# OpenTallas memory compiler (tools/mem_compiler), ASAP7 abstract view
VERSION 5.7 ;
BUSBITCHARS "[]" ;
DIVIDERCHAR "/" ;
PROPERTYDEFINITIONS
  MACRO width INTEGER ;
  MACRO depth INTEGER ;
  MACRO banks INTEGER ;
END PROPERTYDEFINITIONS
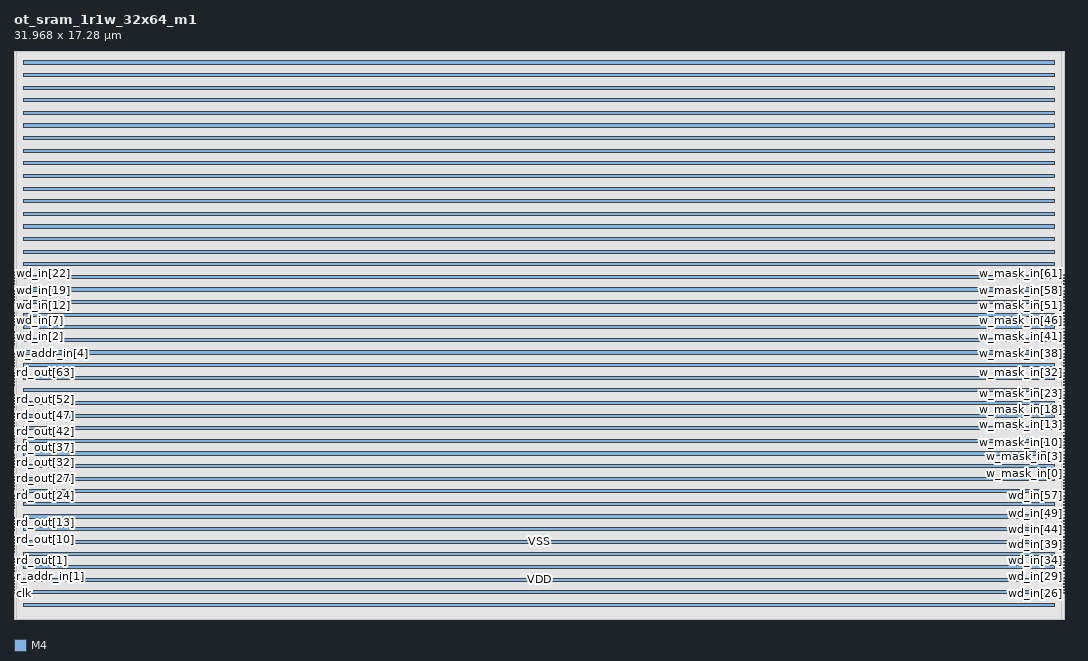
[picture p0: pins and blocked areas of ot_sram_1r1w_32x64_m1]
MACRO ot_sram_1r1w_32x64_m1
  PROPERTY width 64 ;
  PROPERTY depth 32 ;
  PROPERTY banks 1 ;
  FOREIGN ot_sram_1r1w_32x64_m1 0 0 ;
  SYMMETRY X Y R90 ;
  SIZE 31.968 BY 17.280 ;
  CLASS BLOCK ;
  PIN clk
    DIRECTION INPUT ;
    USE CLOCK ;
    SHAPE ABUTMENT ;
    PORT
      LAYER M4 ;
      RECT 0.000 0.768 0.024 0.792 ;
    END
  END clk
  PIN r_ce_in
    DIRECTION INPUT ;
    USE SIGNAL ;
    SHAPE ABUTMENT ;
    PORT
      LAYER M4 ;
      RECT 0.000 0.864 0.024 0.888 ;
    END
  END r_ce_in
  PIN r_addr_in[0]
    DIRECTION INPUT ;
    USE SIGNAL ;
    SHAPE ABUTMENT ;
    PORT
      LAYER M4 ;
      RECT 0.000 0.960 0.024 0.984 ;
    END
  END r_addr_in[0]
  PIN r_addr_in[1]
    DIRECTION INPUT ;
    USE SIGNAL ;
    SHAPE ABUTMENT ;
    PORT
      LAYER M4 ;
      RECT 0.000 1.056 0.024 1.080 ;
    END
  END r_addr_in[1]
  PIN r_addr_in[2]
    DIRECTION INPUT ;
    USE SIGNAL ;
    SHAPE ABUTMENT ;
    PORT
      LAYER M4 ;
      RECT 0.000 1.152 0.024 1.176 ;
    END
  END r_addr_in[2]
  PIN r_addr_in[3]
    DIRECTION INPUT ;
    USE SIGNAL ;
    SHAPE ABUTMENT ;
    PORT
      LAYER M4 ;
      RECT 0.000 1.248 0.024 1.272 ;
    END
  END r_addr_in[3]
  PIN r_addr_in[4]
    DIRECTION INPUT ;
    USE SIGNAL ;
    SHAPE ABUTMENT ;
    PORT
      LAYER M4 ;
      RECT 0.000 1.344 0.024 1.368 ;
    END
  END r_addr_in[4]
  PIN rd_out[0]
    DIRECTION OUTPUT ;
    USE SIGNAL ;
    SHAPE ABUTMENT ;
    PORT
      LAYER M4 ;
      RECT 0.000 1.440 0.024 1.464 ;
    END
  END rd_out[0]
  PIN rd_out[1]
    DIRECTION OUTPUT ;
    USE SIGNAL ;
    SHAPE ABUTMENT ;
    PORT
      LAYER M4 ;
      RECT 0.000 1.536 0.024 1.560 ;
    END
  END rd_out[1]
  PIN rd_out[2]
    DIRECTION OUTPUT ;
    USE SIGNAL ;
    SHAPE ABUTMENT ;
    PORT
      LAYER M4 ;
      RECT 0.000 1.632 0.024 1.656 ;
    END
  END rd_out[2]
  PIN rd_out[3]
    DIRECTION OUTPUT ;
    USE SIGNAL ;
    SHAPE ABUTMENT ;
    PORT
      LAYER M4 ;
      RECT 0.000 1.728 0.024 1.752 ;
    END
  END rd_out[3]
  PIN rd_out[4]
    DIRECTION OUTPUT ;
    USE SIGNAL ;
    SHAPE ABUTMENT ;
    PORT
      LAYER M4 ;
      RECT 0.000 1.824 0.024 1.848 ;
    END
  END rd_out[4]
  PIN rd_out[5]
    DIRECTION OUTPUT ;
    USE SIGNAL ;
    SHAPE ABUTMENT ;
    PORT
      LAYER M4 ;
      RECT 0.000 1.920 0.024 1.944 ;
    END
  END rd_out[5]
  PIN rd_out[6]
    DIRECTION OUTPUT ;
    USE SIGNAL ;
    SHAPE ABUTMENT ;
    PORT
      LAYER M4 ;
      RECT 0.000 2.016 0.024 2.040 ;
    END
  END rd_out[6]
  PIN rd_out[7]
    DIRECTION OUTPUT ;
    USE SIGNAL ;
    SHAPE ABUTMENT ;
    PORT
      LAYER M4 ;
      RECT 0.000 2.112 0.024 2.136 ;
    END
  END rd_out[7]
  PIN rd_out[8]
    DIRECTION OUTPUT ;
    USE SIGNAL ;
    SHAPE ABUTMENT ;
    PORT
      LAYER M4 ;
      RECT 0.000 2.208 0.024 2.232 ;
    END
  END rd_out[8]
  PIN rd_out[9]
    DIRECTION OUTPUT ;
    USE SIGNAL ;
    SHAPE ABUTMENT ;
    PORT
      LAYER M4 ;
      RECT 0.000 2.304 0.024 2.328 ;
    END
  END rd_out[9]
  PIN rd_out[10]
    DIRECTION OUTPUT ;
    USE SIGNAL ;
    SHAPE ABUTMENT ;
    PORT
      LAYER M4 ;
      RECT 0.000 2.400 0.024 2.424 ;
    END
  END rd_out[10]
  PIN rd_out[11]
    DIRECTION OUTPUT ;
    USE SIGNAL ;
    SHAPE ABUTMENT ;
    PORT
      LAYER M4 ;
      RECT 0.000 2.496 0.024 2.520 ;
    END
  END rd_out[11]
  PIN rd_out[12]
    DIRECTION OUTPUT ;
    USE SIGNAL ;
    SHAPE ABUTMENT ;
    PORT
      LAYER M4 ;
      RECT 0.000 2.592 0.024 2.616 ;
    END
  END rd_out[12]
  PIN rd_out[13]
    DIRECTION OUTPUT ;
    USE SIGNAL ;
    SHAPE ABUTMENT ;
    PORT
      LAYER M4 ;
      RECT 0.000 2.688 0.024 2.712 ;
    END
  END rd_out[13]
  PIN rd_out[14]
    DIRECTION OUTPUT ;
    USE SIGNAL ;
    SHAPE ABUTMENT ;
    PORT
      LAYER M4 ;
      RECT 0.000 2.784 0.024 2.808 ;
    END
  END rd_out[14]
  PIN rd_out[15]
    DIRECTION OUTPUT ;
    USE SIGNAL ;
    SHAPE ABUTMENT ;
    PORT
      LAYER M4 ;
      RECT 0.000 2.880 0.024 2.904 ;
    END
  END rd_out[15]
  PIN rd_out[16]
    DIRECTION OUTPUT ;
    USE SIGNAL ;
    SHAPE ABUTMENT ;
    PORT
      LAYER M4 ;
      RECT 0.000 2.976 0.024 3.000 ;
    END
  END rd_out[16]
  PIN rd_out[17]
    DIRECTION OUTPUT ;
    USE SIGNAL ;
    SHAPE ABUTMENT ;
    PORT
      LAYER M4 ;
      RECT 0.000 3.072 0.024 3.096 ;
    END
  END rd_out[17]
  PIN rd_out[18]
    DIRECTION OUTPUT ;
    USE SIGNAL ;
    SHAPE ABUTMENT ;
    PORT
      LAYER M4 ;
      RECT 0.000 3.168 0.024 3.192 ;
    END
  END rd_out[18]
  PIN rd_out[19]
    DIRECTION OUTPUT ;
    USE SIGNAL ;
    SHAPE ABUTMENT ;
    PORT
      LAYER M4 ;
      RECT 0.000 3.264 0.024 3.288 ;
    END
  END rd_out[19]
  PIN rd_out[20]
    DIRECTION OUTPUT ;
    USE SIGNAL ;
    SHAPE ABUTMENT ;
    PORT
      LAYER M4 ;
      RECT 0.000 3.360 0.024 3.384 ;
    END
  END rd_out[20]
  PIN rd_out[21]
    DIRECTION OUTPUT ;
    USE SIGNAL ;
    SHAPE ABUTMENT ;
    PORT
      LAYER M4 ;
      RECT 0.000 3.456 0.024 3.480 ;
    END
  END rd_out[21]
  PIN rd_out[22]
    DIRECTION OUTPUT ;
    USE SIGNAL ;
    SHAPE ABUTMENT ;
    PORT
      LAYER M4 ;
      RECT 0.000 3.552 0.024 3.576 ;
    END
  END rd_out[22]
  PIN rd_out[23]
    DIRECTION OUTPUT ;
    USE SIGNAL ;
    SHAPE ABUTMENT ;
    PORT
      LAYER M4 ;
      RECT 0.000 3.648 0.024 3.672 ;
    END
  END rd_out[23]
  PIN rd_out[24]
    DIRECTION OUTPUT ;
    USE SIGNAL ;
    SHAPE ABUTMENT ;
    PORT
      LAYER M4 ;
      RECT 0.000 3.744 0.024 3.768 ;
    END
  END rd_out[24]
  PIN rd_out[25]
    DIRECTION OUTPUT ;
    USE SIGNAL ;
    SHAPE ABUTMENT ;
    PORT
      LAYER M4 ;
      RECT 0.000 3.840 0.024 3.864 ;
    END
  END rd_out[25]
  PIN rd_out[26]
    DIRECTION OUTPUT ;
    USE SIGNAL ;
    SHAPE ABUTMENT ;
    PORT
      LAYER M4 ;
      RECT 0.000 3.936 0.024 3.960 ;
    END
  END rd_out[26]
  PIN rd_out[27]
    DIRECTION OUTPUT ;
    USE SIGNAL ;
    SHAPE ABUTMENT ;
    PORT
      LAYER M4 ;
      RECT 0.000 4.032 0.024 4.056 ;
    END
  END rd_out[27]
  PIN rd_out[28]
    DIRECTION OUTPUT ;
    USE SIGNAL ;
    SHAPE ABUTMENT ;
    PORT
      LAYER M4 ;
      RECT 0.000 4.128 0.024 4.152 ;
    END
  END rd_out[28]
  PIN rd_out[29]
    DIRECTION OUTPUT ;
    USE SIGNAL ;
    SHAPE ABUTMENT ;
    PORT
      LAYER M4 ;
      RECT 0.000 4.224 0.024 4.248 ;
    END
  END rd_out[29]
  PIN rd_out[30]
    DIRECTION OUTPUT ;
    USE SIGNAL ;
    SHAPE ABUTMENT ;
    PORT
      LAYER M4 ;
      RECT 0.000 4.320 0.024 4.344 ;
    END
  END rd_out[30]
  PIN rd_out[31]
    DIRECTION OUTPUT ;
    USE SIGNAL ;
    SHAPE ABUTMENT ;
    PORT
      LAYER M4 ;
      RECT 0.000 4.416 0.024 4.440 ;
    END
  END rd_out[31]
  PIN rd_out[32]
    DIRECTION OUTPUT ;
    USE SIGNAL ;
    SHAPE ABUTMENT ;
    PORT
      LAYER M4 ;
      RECT 0.000 4.512 0.024 4.536 ;
    END
  END rd_out[32]
  PIN rd_out[33]
    DIRECTION OUTPUT ;
    USE SIGNAL ;
    SHAPE ABUTMENT ;
    PORT
      LAYER M4 ;
      RECT 0.000 4.608 0.024 4.632 ;
    END
  END rd_out[33]
  PIN rd_out[34]
    DIRECTION OUTPUT ;
    USE SIGNAL ;
    SHAPE ABUTMENT ;
    PORT
      LAYER M4 ;
      RECT 0.000 4.704 0.024 4.728 ;
    END
  END rd_out[34]
  PIN rd_out[35]
    DIRECTION OUTPUT ;
    USE SIGNAL ;
    SHAPE ABUTMENT ;
    PORT
      LAYER M4 ;
      RECT 0.000 4.800 0.024 4.824 ;
    END
  END rd_out[35]
  PIN rd_out[36]
    DIRECTION OUTPUT ;
    USE SIGNAL ;
    SHAPE ABUTMENT ;
    PORT
      LAYER M4 ;
      RECT 0.000 4.896 0.024 4.920 ;
    END
  END rd_out[36]
  PIN rd_out[37]
    DIRECTION OUTPUT ;
    USE SIGNAL ;
    SHAPE ABUTMENT ;
    PORT
      LAYER M4 ;
      RECT 0.000 4.992 0.024 5.016 ;
    END
  END rd_out[37]
  PIN rd_out[38]
    DIRECTION OUTPUT ;
    USE SIGNAL ;
    SHAPE ABUTMENT ;
    PORT
      LAYER M4 ;
      RECT 0.000 5.088 0.024 5.112 ;
    END
  END rd_out[38]
  PIN rd_out[39]
    DIRECTION OUTPUT ;
    USE SIGNAL ;
    SHAPE ABUTMENT ;
    PORT
      LAYER M4 ;
      RECT 0.000 5.184 0.024 5.208 ;
    END
  END rd_out[39]
  PIN rd_out[40]
    DIRECTION OUTPUT ;
    USE SIGNAL ;
    SHAPE ABUTMENT ;
    PORT
      LAYER M4 ;
      RECT 0.000 5.280 0.024 5.304 ;
    END
  END rd_out[40]
  PIN rd_out[41]
    DIRECTION OUTPUT ;
    USE SIGNAL ;
    SHAPE ABUTMENT ;
    PORT
      LAYER M4 ;
      RECT 0.000 5.376 0.024 5.400 ;
    END
  END rd_out[41]
  PIN rd_out[42]
    DIRECTION OUTPUT ;
    USE SIGNAL ;
    SHAPE ABUTMENT ;
    PORT
      LAYER M4 ;
      RECT 0.000 5.472 0.024 5.496 ;
    END
  END rd_out[42]
  PIN rd_out[43]
    DIRECTION OUTPUT ;
    USE SIGNAL ;
    SHAPE ABUTMENT ;
    PORT
      LAYER M4 ;
      RECT 0.000 5.568 0.024 5.592 ;
    END
  END rd_out[43]
  PIN rd_out[44]
    DIRECTION OUTPUT ;
    USE SIGNAL ;
    SHAPE ABUTMENT ;
    PORT
      LAYER M4 ;
      RECT 0.000 5.664 0.024 5.688 ;
    END
  END rd_out[44]
  PIN rd_out[45]
    DIRECTION OUTPUT ;
    USE SIGNAL ;
    SHAPE ABUTMENT ;
    PORT
      LAYER M4 ;
      RECT 0.000 5.760 0.024 5.784 ;
    END
  END rd_out[45]
  PIN rd_out[46]
    DIRECTION OUTPUT ;
    USE SIGNAL ;
    SHAPE ABUTMENT ;
    PORT
      LAYER M4 ;
      RECT 0.000 5.856 0.024 5.880 ;
    END
  END rd_out[46]
  PIN rd_out[47]
    DIRECTION OUTPUT ;
    USE SIGNAL ;
    SHAPE ABUTMENT ;
    PORT
      LAYER M4 ;
      RECT 0.000 5.952 0.024 5.976 ;
    END
  END rd_out[47]
  PIN rd_out[48]
    DIRECTION OUTPUT ;
    USE SIGNAL ;
    SHAPE ABUTMENT ;
    PORT
      LAYER M4 ;
      RECT 0.000 6.048 0.024 6.072 ;
    END
  END rd_out[48]
  PIN rd_out[49]
    DIRECTION OUTPUT ;
    USE SIGNAL ;
    SHAPE ABUTMENT ;
    PORT
      LAYER M4 ;
      RECT 0.000 6.144 0.024 6.168 ;
    END
  END rd_out[49]
  PIN rd_out[50]
    DIRECTION OUTPUT ;
    USE SIGNAL ;
    SHAPE ABUTMENT ;
    PORT
      LAYER M4 ;
      RECT 0.000 6.240 0.024 6.264 ;
    END
  END rd_out[50]
  PIN rd_out[51]
    DIRECTION OUTPUT ;
    USE SIGNAL ;
    SHAPE ABUTMENT ;
    PORT
      LAYER M4 ;
      RECT 0.000 6.336 0.024 6.360 ;
    END
  END rd_out[51]
  PIN rd_out[52]
    DIRECTION OUTPUT ;
    USE SIGNAL ;
    SHAPE ABUTMENT ;
    PORT
      LAYER M4 ;
      RECT 0.000 6.432 0.024 6.456 ;
    END
  END rd_out[52]
  PIN rd_out[53]
    DIRECTION OUTPUT ;
    USE SIGNAL ;
    SHAPE ABUTMENT ;
    PORT
      LAYER M4 ;
      RECT 0.000 6.528 0.024 6.552 ;
    END
  END rd_out[53]
  PIN rd_out[54]
    DIRECTION OUTPUT ;
    USE SIGNAL ;
    SHAPE ABUTMENT ;
    PORT
      LAYER M4 ;
      RECT 0.000 6.624 0.024 6.648 ;
    END
  END rd_out[54]
  PIN rd_out[55]
    DIRECTION OUTPUT ;
    USE SIGNAL ;
    SHAPE ABUTMENT ;
    PORT
      LAYER M4 ;
      RECT 0.000 6.720 0.024 6.744 ;
    END
  END rd_out[55]
  PIN rd_out[56]
    DIRECTION OUTPUT ;
    USE SIGNAL ;
    SHAPE ABUTMENT ;
    PORT
      LAYER M4 ;
      RECT 0.000 6.816 0.024 6.840 ;
    END
  END rd_out[56]
  PIN rd_out[57]
    DIRECTION OUTPUT ;
    USE SIGNAL ;
    SHAPE ABUTMENT ;
    PORT
      LAYER M4 ;
      RECT 0.000 6.912 0.024 6.936 ;
    END
  END rd_out[57]
  PIN rd_out[58]
    DIRECTION OUTPUT ;
    USE SIGNAL ;
    SHAPE ABUTMENT ;
    PORT
      LAYER M4 ;
      RECT 0.000 7.008 0.024 7.032 ;
    END
  END rd_out[58]
  PIN rd_out[59]
    DIRECTION OUTPUT ;
    USE SIGNAL ;
    SHAPE ABUTMENT ;
    PORT
      LAYER M4 ;
      RECT 0.000 7.104 0.024 7.128 ;
    END
  END rd_out[59]
  PIN rd_out[60]
    DIRECTION OUTPUT ;
    USE SIGNAL ;
    SHAPE ABUTMENT ;
    PORT
      LAYER M4 ;
      RECT 0.000 7.200 0.024 7.224 ;
    END
  END rd_out[60]
  PIN rd_out[61]
    DIRECTION OUTPUT ;
    USE SIGNAL ;
    SHAPE ABUTMENT ;
    PORT
      LAYER M4 ;
      RECT 0.000 7.296 0.024 7.320 ;
    END
  END rd_out[61]
  PIN rd_out[62]
    DIRECTION OUTPUT ;
    USE SIGNAL ;
    SHAPE ABUTMENT ;
    PORT
      LAYER M4 ;
      RECT 0.000 7.392 0.024 7.416 ;
    END
  END rd_out[62]
  PIN rd_out[63]
    DIRECTION OUTPUT ;
    USE SIGNAL ;
    SHAPE ABUTMENT ;
    PORT
      LAYER M4 ;
      RECT 0.000 7.488 0.024 7.512 ;
    END
  END rd_out[63]
  PIN w_ce_in
    DIRECTION INPUT ;
    USE SIGNAL ;
    SHAPE ABUTMENT ;
    PORT
      LAYER M4 ;
      RECT 0.000 7.584 0.024 7.608 ;
    END
  END w_ce_in
  PIN w_addr_in[0]
    DIRECTION INPUT ;
    USE SIGNAL ;
    SHAPE ABUTMENT ;
    PORT
      LAYER M4 ;
      RECT 0.000 7.680 0.024 7.704 ;
    END
  END w_addr_in[0]
  PIN w_addr_in[1]
    DIRECTION INPUT ;
    USE SIGNAL ;
    SHAPE ABUTMENT ;
    PORT
      LAYER M4 ;
      RECT 0.000 7.776 0.024 7.800 ;
    END
  END w_addr_in[1]
  PIN w_addr_in[2]
    DIRECTION INPUT ;
    USE SIGNAL ;
    SHAPE ABUTMENT ;
    PORT
      LAYER M4 ;
      RECT 0.000 7.872 0.024 7.896 ;
    END
  END w_addr_in[2]
  PIN w_addr_in[3]
    DIRECTION INPUT ;
    USE SIGNAL ;
    SHAPE ABUTMENT ;
    PORT
      LAYER M4 ;
      RECT 0.000 7.968 0.024 7.992 ;
    END
  END w_addr_in[3]
  PIN w_addr_in[4]
    DIRECTION INPUT ;
    USE SIGNAL ;
    SHAPE ABUTMENT ;
    PORT
      LAYER M4 ;
      RECT 0.000 8.064 0.024 8.088 ;
    END
  END w_addr_in[4]
  PIN wd_in[0]
    DIRECTION INPUT ;
    USE SIGNAL ;
    SHAPE ABUTMENT ;
    PORT
      LAYER M4 ;
      RECT 0.000 8.160 0.024 8.184 ;
    END
  END wd_in[0]
  PIN wd_in[1]
    DIRECTION INPUT ;
    USE SIGNAL ;
    SHAPE ABUTMENT ;
    PORT
      LAYER M4 ;
      RECT 0.000 8.256 0.024 8.280 ;
    END
  END wd_in[1]
  PIN wd_in[2]
    DIRECTION INPUT ;
    USE SIGNAL ;
    SHAPE ABUTMENT ;
    PORT
      LAYER M4 ;
      RECT 0.000 8.352 0.024 8.376 ;
    END
  END wd_in[2]
  PIN wd_in[3]
    DIRECTION INPUT ;
    USE SIGNAL ;
    SHAPE ABUTMENT ;
    PORT
      LAYER M4 ;
      RECT 0.000 8.448 0.024 8.472 ;
    END
  END wd_in[3]
  PIN wd_in[4]
    DIRECTION INPUT ;
    USE SIGNAL ;
    SHAPE ABUTMENT ;
    PORT
      LAYER M4 ;
      RECT 0.000 8.544 0.024 8.568 ;
    END
  END wd_in[4]
  PIN wd_in[5]
    DIRECTION INPUT ;
    USE SIGNAL ;
    SHAPE ABUTMENT ;
    PORT
      LAYER M4 ;
      RECT 0.000 8.640 0.024 8.664 ;
    END
  END wd_in[5]
  PIN wd_in[6]
    DIRECTION INPUT ;
    USE SIGNAL ;
    SHAPE ABUTMENT ;
    PORT
      LAYER M4 ;
      RECT 0.000 8.736 0.024 8.760 ;
    END
  END wd_in[6]
  PIN wd_in[7]
    DIRECTION INPUT ;
    USE SIGNAL ;
    SHAPE ABUTMENT ;
    PORT
      LAYER M4 ;
      RECT 0.000 8.832 0.024 8.856 ;
    END
  END wd_in[7]
  PIN wd_in[8]
    DIRECTION INPUT ;
    USE SIGNAL ;
    SHAPE ABUTMENT ;
    PORT
      LAYER M4 ;
      RECT 0.000 8.928 0.024 8.952 ;
    END
  END wd_in[8]
  PIN wd_in[9]
    DIRECTION INPUT ;
    USE SIGNAL ;
    SHAPE ABUTMENT ;
    PORT
      LAYER M4 ;
      RECT 0.000 9.024 0.024 9.048 ;
    END
  END wd_in[9]
  PIN wd_in[10]
    DIRECTION INPUT ;
    USE SIGNAL ;
    SHAPE ABUTMENT ;
    PORT
      LAYER M4 ;
      RECT 0.000 9.120 0.024 9.144 ;
    END
  END wd_in[10]
  PIN wd_in[11]
    DIRECTION INPUT ;
    USE SIGNAL ;
    SHAPE ABUTMENT ;
    PORT
      LAYER M4 ;
      RECT 0.000 9.216 0.024 9.240 ;
    END
  END wd_in[11]
  PIN wd_in[12]
    DIRECTION INPUT ;
    USE SIGNAL ;
    SHAPE ABUTMENT ;
    PORT
      LAYER M4 ;
      RECT 0.000 9.312 0.024 9.336 ;
    END
  END wd_in[12]
  PIN wd_in[13]
    DIRECTION INPUT ;
    USE SIGNAL ;
    SHAPE ABUTMENT ;
    PORT
      LAYER M4 ;
      RECT 0.000 9.408 0.024 9.432 ;
    END
  END wd_in[13]
  PIN wd_in[14]
    DIRECTION INPUT ;
    USE SIGNAL ;
    SHAPE ABUTMENT ;
    PORT
      LAYER M4 ;
      RECT 0.000 9.504 0.024 9.528 ;
    END
  END wd_in[14]
  PIN wd_in[15]
    DIRECTION INPUT ;
    USE SIGNAL ;
    SHAPE ABUTMENT ;
    PORT
      LAYER M4 ;
      RECT 0.000 9.600 0.024 9.624 ;
    END
  END wd_in[15]
  PIN wd_in[16]
    DIRECTION INPUT ;
    USE SIGNAL ;
    SHAPE ABUTMENT ;
    PORT
      LAYER M4 ;
      RECT 0.000 9.696 0.024 9.720 ;
    END
  END wd_in[16]
  PIN wd_in[17]
    DIRECTION INPUT ;
    USE SIGNAL ;
    SHAPE ABUTMENT ;
    PORT
      LAYER M4 ;
      RECT 0.000 9.792 0.024 9.816 ;
    END
  END wd_in[17]
  PIN wd_in[18]
    DIRECTION INPUT ;
    USE SIGNAL ;
    SHAPE ABUTMENT ;
    PORT
      LAYER M4 ;
      RECT 0.000 9.888 0.024 9.912 ;
    END
  END wd_in[18]
  PIN wd_in[19]
    DIRECTION INPUT ;
    USE SIGNAL ;
    SHAPE ABUTMENT ;
    PORT
      LAYER M4 ;
      RECT 0.000 9.984 0.024 10.008 ;
    END
  END wd_in[19]
  PIN wd_in[20]
    DIRECTION INPUT ;
    USE SIGNAL ;
    SHAPE ABUTMENT ;
    PORT
      LAYER M4 ;
      RECT 0.000 10.080 0.024 10.104 ;
    END
  END wd_in[20]
  PIN wd_in[21]
    DIRECTION INPUT ;
    USE SIGNAL ;
    SHAPE ABUTMENT ;
    PORT
      LAYER M4 ;
      RECT 0.000 10.176 0.024 10.200 ;
    END
  END wd_in[21]
  PIN wd_in[22]
    DIRECTION INPUT ;
    USE SIGNAL ;
    SHAPE ABUTMENT ;
    PORT
      LAYER M4 ;
      RECT 0.000 10.272 0.024 10.296 ;
    END
  END wd_in[22]
  PIN wd_in[23]
    DIRECTION INPUT ;
    USE SIGNAL ;
    SHAPE ABUTMENT ;
    PORT
      LAYER M4 ;
      RECT 0.000 10.368 0.024 10.392 ;
    END
  END wd_in[23]
  PIN wd_in[24]
    DIRECTION INPUT ;
    USE SIGNAL ;
    SHAPE ABUTMENT ;
    PORT
      LAYER M4 ;
      RECT 0.000 10.464 0.024 10.488 ;
    END
  END wd_in[24]
  PIN wd_in[25]
    DIRECTION INPUT ;
    USE SIGNAL ;
    SHAPE ABUTMENT ;
    PORT
      LAYER M4 ;
      RECT 0.000 10.560 0.024 10.584 ;
    END
  END wd_in[25]
  PIN wd_in[26]
    DIRECTION INPUT ;
    USE SIGNAL ;
    SHAPE ABUTMENT ;
    PORT
      LAYER M4 ;
      RECT 31.944 0.768 31.968 0.792 ;
    END
  END wd_in[26]
  PIN wd_in[27]
    DIRECTION INPUT ;
    USE SIGNAL ;
    SHAPE ABUTMENT ;
    PORT
      LAYER M4 ;
      RECT 31.944 0.864 31.968 0.888 ;
    END
  END wd_in[27]
  PIN wd_in[28]
    DIRECTION INPUT ;
    USE SIGNAL ;
    SHAPE ABUTMENT ;
    PORT
      LAYER M4 ;
      RECT 31.944 0.960 31.968 0.984 ;
    END
  END wd_in[28]
  PIN wd_in[29]
    DIRECTION INPUT ;
    USE SIGNAL ;
    SHAPE ABUTMENT ;
    PORT
      LAYER M4 ;
      RECT 31.944 1.056 31.968 1.080 ;
    END
  END wd_in[29]
  PIN wd_in[30]
    DIRECTION INPUT ;
    USE SIGNAL ;
    SHAPE ABUTMENT ;
    PORT
      LAYER M4 ;
      RECT 31.944 1.152 31.968 1.176 ;
    END
  END wd_in[30]
  PIN wd_in[31]
    DIRECTION INPUT ;
    USE SIGNAL ;
    SHAPE ABUTMENT ;
    PORT
      LAYER M4 ;
      RECT 31.944 1.248 31.968 1.272 ;
    END
  END wd_in[31]
  PIN wd_in[32]
    DIRECTION INPUT ;
    USE SIGNAL ;
    SHAPE ABUTMENT ;
    PORT
      LAYER M4 ;
      RECT 31.944 1.344 31.968 1.368 ;
    END
  END wd_in[32]
  PIN wd_in[33]
    DIRECTION INPUT ;
    USE SIGNAL ;
    SHAPE ABUTMENT ;
    PORT
      LAYER M4 ;
      RECT 31.944 1.440 31.968 1.464 ;
    END
  END wd_in[33]
  PIN wd_in[34]
    DIRECTION INPUT ;
    USE SIGNAL ;
    SHAPE ABUTMENT ;
    PORT
      LAYER M4 ;
      RECT 31.944 1.536 31.968 1.560 ;
    END
  END wd_in[34]
  PIN wd_in[35]
    DIRECTION INPUT ;
    USE SIGNAL ;
    SHAPE ABUTMENT ;
    PORT
      LAYER M4 ;
      RECT 31.944 1.632 31.968 1.656 ;
    END
  END wd_in[35]
  PIN wd_in[36]
    DIRECTION INPUT ;
    USE SIGNAL ;
    SHAPE ABUTMENT ;
    PORT
      LAYER M4 ;
      RECT 31.944 1.728 31.968 1.752 ;
    END
  END wd_in[36]
  PIN wd_in[37]
    DIRECTION INPUT ;
    USE SIGNAL ;
    SHAPE ABUTMENT ;
    PORT
      LAYER M4 ;
      RECT 31.944 1.824 31.968 1.848 ;
    END
  END wd_in[37]
  PIN wd_in[38]
    DIRECTION INPUT ;
    USE SIGNAL ;
    SHAPE ABUTMENT ;
    PORT
      LAYER M4 ;
      RECT 31.944 1.920 31.968 1.944 ;
    END
  END wd_in[38]
  PIN wd_in[39]
    DIRECTION INPUT ;
    USE SIGNAL ;
    SHAPE ABUTMENT ;
    PORT
      LAYER M4 ;
      RECT 31.944 2.016 31.968 2.040 ;
    END
  END wd_in[39]
  PIN wd_in[40]
    DIRECTION INPUT ;
    USE SIGNAL ;
    SHAPE ABUTMENT ;
    PORT
      LAYER M4 ;
      RECT 31.944 2.112 31.968 2.136 ;
    END
  END wd_in[40]
  PIN wd_in[41]
    DIRECTION INPUT ;
    USE SIGNAL ;
    SHAPE ABUTMENT ;
    PORT
      LAYER M4 ;
      RECT 31.944 2.208 31.968 2.232 ;
    END
  END wd_in[41]
  PIN wd_in[42]
    DIRECTION INPUT ;
    USE SIGNAL ;
    SHAPE ABUTMENT ;
    PORT
      LAYER M4 ;
      RECT 31.944 2.304 31.968 2.328 ;
    END
  END wd_in[42]
  PIN wd_in[43]
    DIRECTION INPUT ;
    USE SIGNAL ;
    SHAPE ABUTMENT ;
    PORT
      LAYER M4 ;
      RECT 31.944 2.400 31.968 2.424 ;
    END
  END wd_in[43]
  PIN wd_in[44]
    DIRECTION INPUT ;
    USE SIGNAL ;
    SHAPE ABUTMENT ;
    PORT
      LAYER M4 ;
      RECT 31.944 2.496 31.968 2.520 ;
    END
  END wd_in[44]
  PIN wd_in[45]
    DIRECTION INPUT ;
    USE SIGNAL ;
    SHAPE ABUTMENT ;
    PORT
      LAYER M4 ;
      RECT 31.944 2.592 31.968 2.616 ;
    END
  END wd_in[45]
  PIN wd_in[46]
    DIRECTION INPUT ;
    USE SIGNAL ;
    SHAPE ABUTMENT ;
    PORT
      LAYER M4 ;
      RECT 31.944 2.688 31.968 2.712 ;
    END
  END wd_in[46]
  PIN wd_in[47]
    DIRECTION INPUT ;
    USE SIGNAL ;
    SHAPE ABUTMENT ;
    PORT
      LAYER M4 ;
      RECT 31.944 2.784 31.968 2.808 ;
    END
  END wd_in[47]
  PIN wd_in[48]
    DIRECTION INPUT ;
    USE SIGNAL ;
    SHAPE ABUTMENT ;
    PORT
      LAYER M4 ;
      RECT 31.944 2.880 31.968 2.904 ;
    END
  END wd_in[48]
  PIN wd_in[49]
    DIRECTION INPUT ;
    USE SIGNAL ;
    SHAPE ABUTMENT ;
    PORT
      LAYER M4 ;
      RECT 31.944 2.976 31.968 3.000 ;
    END
  END wd_in[49]
  PIN wd_in[50]
    DIRECTION INPUT ;
    USE SIGNAL ;
    SHAPE ABUTMENT ;
    PORT
      LAYER M4 ;
      RECT 31.944 3.072 31.968 3.096 ;
    END
  END wd_in[50]
  PIN wd_in[51]
    DIRECTION INPUT ;
    USE SIGNAL ;
    SHAPE ABUTMENT ;
    PORT
      LAYER M4 ;
      RECT 31.944 3.168 31.968 3.192 ;
    END
  END wd_in[51]
  PIN wd_in[52]
    DIRECTION INPUT ;
    USE SIGNAL ;
    SHAPE ABUTMENT ;
    PORT
      LAYER M4 ;
      RECT 31.944 3.264 31.968 3.288 ;
    END
  END wd_in[52]
  PIN wd_in[53]
    DIRECTION INPUT ;
    USE SIGNAL ;
    SHAPE ABUTMENT ;
    PORT
      LAYER M4 ;
      RECT 31.944 3.360 31.968 3.384 ;
    END
  END wd_in[53]
  PIN wd_in[54]
    DIRECTION INPUT ;
    USE SIGNAL ;
    SHAPE ABUTMENT ;
    PORT
      LAYER M4 ;
      RECT 31.944 3.456 31.968 3.480 ;
    END
  END wd_in[54]
  PIN wd_in[55]
    DIRECTION INPUT ;
    USE SIGNAL ;
    SHAPE ABUTMENT ;
    PORT
      LAYER M4 ;
      RECT 31.944 3.552 31.968 3.576 ;
    END
  END wd_in[55]
  PIN wd_in[56]
    DIRECTION INPUT ;
    USE SIGNAL ;
    SHAPE ABUTMENT ;
    PORT
      LAYER M4 ;
      RECT 31.944 3.648 31.968 3.672 ;
    END
  END wd_in[56]
  PIN wd_in[57]
    DIRECTION INPUT ;
    USE SIGNAL ;
    SHAPE ABUTMENT ;
    PORT
      LAYER M4 ;
      RECT 31.944 3.744 31.968 3.768 ;
    END
  END wd_in[57]
  PIN wd_in[58]
    DIRECTION INPUT ;
    USE SIGNAL ;
    SHAPE ABUTMENT ;
    PORT
      LAYER M4 ;
      RECT 31.944 3.840 31.968 3.864 ;
    END
  END wd_in[58]
  PIN wd_in[59]
    DIRECTION INPUT ;
    USE SIGNAL ;
    SHAPE ABUTMENT ;
    PORT
      LAYER M4 ;
      RECT 31.944 3.936 31.968 3.960 ;
    END
  END wd_in[59]
  PIN wd_in[60]
    DIRECTION INPUT ;
    USE SIGNAL ;
    SHAPE ABUTMENT ;
    PORT
      LAYER M4 ;
      RECT 31.944 4.032 31.968 4.056 ;
    END
  END wd_in[60]
  PIN wd_in[61]
    DIRECTION INPUT ;
    USE SIGNAL ;
    SHAPE ABUTMENT ;
    PORT
      LAYER M4 ;
      RECT 31.944 4.128 31.968 4.152 ;
    END
  END wd_in[61]
  PIN wd_in[62]
    DIRECTION INPUT ;
    USE SIGNAL ;
    SHAPE ABUTMENT ;
    PORT
      LAYER M4 ;
      RECT 31.944 4.224 31.968 4.248 ;
    END
  END wd_in[62]
  PIN wd_in[63]
    DIRECTION INPUT ;
    USE SIGNAL ;
    SHAPE ABUTMENT ;
    PORT
      LAYER M4 ;
      RECT 31.944 4.320 31.968 4.344 ;
    END
  END wd_in[63]
  PIN w_mask_in[0]
    DIRECTION INPUT ;
    USE SIGNAL ;
    SHAPE ABUTMENT ;
    PORT
      LAYER M4 ;
      RECT 31.944 4.416 31.968 4.440 ;
    END
  END w_mask_in[0]
  PIN w_mask_in[1]
    DIRECTION INPUT ;
    USE SIGNAL ;
    SHAPE ABUTMENT ;
    PORT
      LAYER M4 ;
      RECT 31.944 4.512 31.968 4.536 ;
    END
  END w_mask_in[1]
  PIN w_mask_in[2]
    DIRECTION INPUT ;
    USE SIGNAL ;
    SHAPE ABUTMENT ;
    PORT
      LAYER M4 ;
      RECT 31.944 4.608 31.968 4.632 ;
    END
  END w_mask_in[2]
  PIN w_mask_in[3]
    DIRECTION INPUT ;
    USE SIGNAL ;
    SHAPE ABUTMENT ;
    PORT
      LAYER M4 ;
      RECT 31.944 4.704 31.968 4.728 ;
    END
  END w_mask_in[3]
  PIN w_mask_in[4]
    DIRECTION INPUT ;
    USE SIGNAL ;
    SHAPE ABUTMENT ;
    PORT
      LAYER M4 ;
      RECT 31.944 4.800 31.968 4.824 ;
    END
  END w_mask_in[4]
  PIN w_mask_in[5]
    DIRECTION INPUT ;
    USE SIGNAL ;
    SHAPE ABUTMENT ;
    PORT
      LAYER M4 ;
      RECT 31.944 4.896 31.968 4.920 ;
    END
  END w_mask_in[5]
  PIN w_mask_in[6]
    DIRECTION INPUT ;
    USE SIGNAL ;
    SHAPE ABUTMENT ;
    PORT
      LAYER M4 ;
      RECT 31.944 4.992 31.968 5.016 ;
    END
  END w_mask_in[6]
  PIN w_mask_in[7]
    DIRECTION INPUT ;
    USE SIGNAL ;
    SHAPE ABUTMENT ;
    PORT
      LAYER M4 ;
      RECT 31.944 5.088 31.968 5.112 ;
    END
  END w_mask_in[7]
  PIN w_mask_in[8]
    DIRECTION INPUT ;
    USE SIGNAL ;
    SHAPE ABUTMENT ;
    PORT
      LAYER M4 ;
      RECT 31.944 5.184 31.968 5.208 ;
    END
  END w_mask_in[8]
  PIN w_mask_in[9]
    DIRECTION INPUT ;
    USE SIGNAL ;
    SHAPE ABUTMENT ;
    PORT
      LAYER M4 ;
      RECT 31.944 5.280 31.968 5.304 ;
    END
  END w_mask_in[9]
  PIN w_mask_in[10]
    DIRECTION INPUT ;
    USE SIGNAL ;
    SHAPE ABUTMENT ;
    PORT
      LAYER M4 ;
      RECT 31.944 5.376 31.968 5.400 ;
    END
  END w_mask_in[10]
  PIN w_mask_in[11]
    DIRECTION INPUT ;
    USE SIGNAL ;
    SHAPE ABUTMENT ;
    PORT
      LAYER M4 ;
      RECT 31.944 5.472 31.968 5.496 ;
    END
  END w_mask_in[11]
  PIN w_mask_in[12]
    DIRECTION INPUT ;
    USE SIGNAL ;
    SHAPE ABUTMENT ;
    PORT
      LAYER M4 ;
      RECT 31.944 5.568 31.968 5.592 ;
    END
  END w_mask_in[12]
  PIN w_mask_in[13]
    DIRECTION INPUT ;
    USE SIGNAL ;
    SHAPE ABUTMENT ;
    PORT
      LAYER M4 ;
      RECT 31.944 5.664 31.968 5.688 ;
    END
  END w_mask_in[13]
  PIN w_mask_in[14]
    DIRECTION INPUT ;
    USE SIGNAL ;
    SHAPE ABUTMENT ;
    PORT
      LAYER M4 ;
      RECT 31.944 5.760 31.968 5.784 ;
    END
  END w_mask_in[14]
  PIN w_mask_in[15]
    DIRECTION INPUT ;
    USE SIGNAL ;
    SHAPE ABUTMENT ;
    PORT
      LAYER M4 ;
      RECT 31.944 5.856 31.968 5.880 ;
    END
  END w_mask_in[15]
  PIN w_mask_in[16]
    DIRECTION INPUT ;
    USE SIGNAL ;
    SHAPE ABUTMENT ;
    PORT
      LAYER M4 ;
      RECT 31.944 5.952 31.968 5.976 ;
    END
  END w_mask_in[16]
  PIN w_mask_in[17]
    DIRECTION INPUT ;
    USE SIGNAL ;
    SHAPE ABUTMENT ;
    PORT
      LAYER M4 ;
      RECT 31.944 6.048 31.968 6.072 ;
    END
  END w_mask_in[17]
  PIN w_mask_in[18]
    DIRECTION INPUT ;
    USE SIGNAL ;
    SHAPE ABUTMENT ;
    PORT
      LAYER M4 ;
      RECT 31.944 6.144 31.968 6.168 ;
    END
  END w_mask_in[18]
  PIN w_mask_in[19]
    DIRECTION INPUT ;
    USE SIGNAL ;
    SHAPE ABUTMENT ;
    PORT
      LAYER M4 ;
      RECT 31.944 6.240 31.968 6.264 ;
    END
  END w_mask_in[19]
  PIN w_mask_in[20]
    DIRECTION INPUT ;
    USE SIGNAL ;
    SHAPE ABUTMENT ;
    PORT
      LAYER M4 ;
      RECT 31.944 6.336 31.968 6.360 ;
    END
  END w_mask_in[20]
  PIN w_mask_in[21]
    DIRECTION INPUT ;
    USE SIGNAL ;
    SHAPE ABUTMENT ;
    PORT
      LAYER M4 ;
      RECT 31.944 6.432 31.968 6.456 ;
    END
  END w_mask_in[21]
  PIN w_mask_in[22]
    DIRECTION INPUT ;
    USE SIGNAL ;
    SHAPE ABUTMENT ;
    PORT
      LAYER M4 ;
      RECT 31.944 6.528 31.968 6.552 ;
    END
  END w_mask_in[22]
  PIN w_mask_in[23]
    DIRECTION INPUT ;
    USE SIGNAL ;
    SHAPE ABUTMENT ;
    PORT
      LAYER M4 ;
      RECT 31.944 6.624 31.968 6.648 ;
    END
  END w_mask_in[23]
  PIN w_mask_in[24]
    DIRECTION INPUT ;
    USE SIGNAL ;
    SHAPE ABUTMENT ;
    PORT
      LAYER M4 ;
      RECT 31.944 6.720 31.968 6.744 ;
    END
  END w_mask_in[24]
  PIN w_mask_in[25]
    DIRECTION INPUT ;
    USE SIGNAL ;
    SHAPE ABUTMENT ;
    PORT
      LAYER M4 ;
      RECT 31.944 6.816 31.968 6.840 ;
    END
  END w_mask_in[25]
  PIN w_mask_in[26]
    DIRECTION INPUT ;
    USE SIGNAL ;
    SHAPE ABUTMENT ;
    PORT
      LAYER M4 ;
      RECT 31.944 6.912 31.968 6.936 ;
    END
  END w_mask_in[26]
  PIN w_mask_in[27]
    DIRECTION INPUT ;
    USE SIGNAL ;
    SHAPE ABUTMENT ;
    PORT
      LAYER M4 ;
      RECT 31.944 7.008 31.968 7.032 ;
    END
  END w_mask_in[27]
  PIN w_mask_in[28]
    DIRECTION INPUT ;
    USE SIGNAL ;
    SHAPE ABUTMENT ;
    PORT
      LAYER M4 ;
      RECT 31.944 7.104 31.968 7.128 ;
    END
  END w_mask_in[28]
  PIN w_mask_in[29]
    DIRECTION INPUT ;
    USE SIGNAL ;
    SHAPE ABUTMENT ;
    PORT
      LAYER M4 ;
      RECT 31.944 7.200 31.968 7.224 ;
    END
  END w_mask_in[29]
  PIN w_mask_in[30]
    DIRECTION INPUT ;
    USE SIGNAL ;
    SHAPE ABUTMENT ;
    PORT
      LAYER M4 ;
      RECT 31.944 7.296 31.968 7.320 ;
    END
  END w_mask_in[30]
  PIN w_mask_in[31]
    DIRECTION INPUT ;
    USE SIGNAL ;
    SHAPE ABUTMENT ;
    PORT
      LAYER M4 ;
      RECT 31.944 7.392 31.968 7.416 ;
    END
  END w_mask_in[31]
  PIN w_mask_in[32]
    DIRECTION INPUT ;
    USE SIGNAL ;
    SHAPE ABUTMENT ;
    PORT
      LAYER M4 ;
      RECT 31.944 7.488 31.968 7.512 ;
    END
  END w_mask_in[32]
  PIN w_mask_in[33]
    DIRECTION INPUT ;
    USE SIGNAL ;
    SHAPE ABUTMENT ;
    PORT
      LAYER M4 ;
      RECT 31.944 7.584 31.968 7.608 ;
    END
  END w_mask_in[33]
  PIN w_mask_in[34]
    DIRECTION INPUT ;
    USE SIGNAL ;
    SHAPE ABUTMENT ;
    PORT
      LAYER M4 ;
      RECT 31.944 7.680 31.968 7.704 ;
    END
  END w_mask_in[34]
  PIN w_mask_in[35]
    DIRECTION INPUT ;
    USE SIGNAL ;
    SHAPE ABUTMENT ;
    PORT
      LAYER M4 ;
      RECT 31.944 7.776 31.968 7.800 ;
    END
  END w_mask_in[35]
  PIN w_mask_in[36]
    DIRECTION INPUT ;
    USE SIGNAL ;
    SHAPE ABUTMENT ;
    PORT
      LAYER M4 ;
      RECT 31.944 7.872 31.968 7.896 ;
    END
  END w_mask_in[36]
  PIN w_mask_in[37]
    DIRECTION INPUT ;
    USE SIGNAL ;
    SHAPE ABUTMENT ;
    PORT
      LAYER M4 ;
      RECT 31.944 7.968 31.968 7.992 ;
    END
  END w_mask_in[37]
  PIN w_mask_in[38]
    DIRECTION INPUT ;
    USE SIGNAL ;
    SHAPE ABUTMENT ;
    PORT
      LAYER M4 ;
      RECT 31.944 8.064 31.968 8.088 ;
    END
  END w_mask_in[38]
  PIN w_mask_in[39]
    DIRECTION INPUT ;
    USE SIGNAL ;
    SHAPE ABUTMENT ;
    PORT
      LAYER M4 ;
      RECT 31.944 8.160 31.968 8.184 ;
    END
  END w_mask_in[39]
  PIN w_mask_in[40]
    DIRECTION INPUT ;
    USE SIGNAL ;
    SHAPE ABUTMENT ;
    PORT
      LAYER M4 ;
      RECT 31.944 8.256 31.968 8.280 ;
    END
  END w_mask_in[40]
  PIN w_mask_in[41]
    DIRECTION INPUT ;
    USE SIGNAL ;
    SHAPE ABUTMENT ;
    PORT
      LAYER M4 ;
      RECT 31.944 8.352 31.968 8.376 ;
    END
  END w_mask_in[41]
  PIN w_mask_in[42]
    DIRECTION INPUT ;
    USE SIGNAL ;
    SHAPE ABUTMENT ;
    PORT
      LAYER M4 ;
      RECT 31.944 8.448 31.968 8.472 ;
    END
  END w_mask_in[42]
  PIN w_mask_in[43]
    DIRECTION INPUT ;
    USE SIGNAL ;
    SHAPE ABUTMENT ;
    PORT
      LAYER M4 ;
      RECT 31.944 8.544 31.968 8.568 ;
    END
  END w_mask_in[43]
  PIN w_mask_in[44]
    DIRECTION INPUT ;
    USE SIGNAL ;
    SHAPE ABUTMENT ;
    PORT
      LAYER M4 ;
      RECT 31.944 8.640 31.968 8.664 ;
    END
  END w_mask_in[44]
  PIN w_mask_in[45]
    DIRECTION INPUT ;
    USE SIGNAL ;
    SHAPE ABUTMENT ;
    PORT
      LAYER M4 ;
      RECT 31.944 8.736 31.968 8.760 ;
    END
  END w_mask_in[45]
  PIN w_mask_in[46]
    DIRECTION INPUT ;
    USE SIGNAL ;
    SHAPE ABUTMENT ;
    PORT
      LAYER M4 ;
      RECT 31.944 8.832 31.968 8.856 ;
    END
  END w_mask_in[46]
  PIN w_mask_in[47]
    DIRECTION INPUT ;
    USE SIGNAL ;
    SHAPE ABUTMENT ;
    PORT
      LAYER M4 ;
      RECT 31.944 8.928 31.968 8.952 ;
    END
  END w_mask_in[47]
  PIN w_mask_in[48]
    DIRECTION INPUT ;
    USE SIGNAL ;
    SHAPE ABUTMENT ;
    PORT
      LAYER M4 ;
      RECT 31.944 9.024 31.968 9.048 ;
    END
  END w_mask_in[48]
  PIN w_mask_in[49]
    DIRECTION INPUT ;
    USE SIGNAL ;
    SHAPE ABUTMENT ;
    PORT
      LAYER M4 ;
      RECT 31.944 9.120 31.968 9.144 ;
    END
  END w_mask_in[49]
  PIN w_mask_in[50]
    DIRECTION INPUT ;
    USE SIGNAL ;
    SHAPE ABUTMENT ;
    PORT
      LAYER M4 ;
      RECT 31.944 9.216 31.968 9.240 ;
    END
  END w_mask_in[50]
  PIN w_mask_in[51]
    DIRECTION INPUT ;
    USE SIGNAL ;
    SHAPE ABUTMENT ;
    PORT
      LAYER M4 ;
      RECT 31.944 9.312 31.968 9.336 ;
    END
  END w_mask_in[51]
  PIN w_mask_in[52]
    DIRECTION INPUT ;
    USE SIGNAL ;
    SHAPE ABUTMENT ;
    PORT
      LAYER M4 ;
      RECT 31.944 9.408 31.968 9.432 ;
    END
  END w_mask_in[52]
  PIN w_mask_in[53]
    DIRECTION INPUT ;
    USE SIGNAL ;
    SHAPE ABUTMENT ;
    PORT
      LAYER M4 ;
      RECT 31.944 9.504 31.968 9.528 ;
    END
  END w_mask_in[53]
  PIN w_mask_in[54]
    DIRECTION INPUT ;
    USE SIGNAL ;
    SHAPE ABUTMENT ;
    PORT
      LAYER M4 ;
      RECT 31.944 9.600 31.968 9.624 ;
    END
  END w_mask_in[54]
  PIN w_mask_in[55]
    DIRECTION INPUT ;
    USE SIGNAL ;
    SHAPE ABUTMENT ;
    PORT
      LAYER M4 ;
      RECT 31.944 9.696 31.968 9.720 ;
    END
  END w_mask_in[55]
  PIN w_mask_in[56]
    DIRECTION INPUT ;
    USE SIGNAL ;
    SHAPE ABUTMENT ;
    PORT
      LAYER M4 ;
      RECT 31.944 9.792 31.968 9.816 ;
    END
  END w_mask_in[56]
  PIN w_mask_in[57]
    DIRECTION INPUT ;
    USE SIGNAL ;
    SHAPE ABUTMENT ;
    PORT
      LAYER M4 ;
      RECT 31.944 9.888 31.968 9.912 ;
    END
  END w_mask_in[57]
  PIN w_mask_in[58]
    DIRECTION INPUT ;
    USE SIGNAL ;
    SHAPE ABUTMENT ;
    PORT
      LAYER M4 ;
      RECT 31.944 9.984 31.968 10.008 ;
    END
  END w_mask_in[58]
  PIN w_mask_in[59]
    DIRECTION INPUT ;
    USE SIGNAL ;
    SHAPE ABUTMENT ;
    PORT
      LAYER M4 ;
      RECT 31.944 10.080 31.968 10.104 ;
    END
  END w_mask_in[59]
  PIN w_mask_in[60]
    DIRECTION INPUT ;
    USE SIGNAL ;
    SHAPE ABUTMENT ;
    PORT
      LAYER M4 ;
      RECT 31.944 10.176 31.968 10.200 ;
    END
  END w_mask_in[60]
  PIN w_mask_in[61]
    DIRECTION INPUT ;
    USE SIGNAL ;
    SHAPE ABUTMENT ;
    PORT
      LAYER M4 ;
      RECT 31.944 10.272 31.968 10.296 ;
    END
  END w_mask_in[61]
  PIN w_mask_in[62]
    DIRECTION INPUT ;
    USE SIGNAL ;
    SHAPE ABUTMENT ;
    PORT
      LAYER M4 ;
      RECT 31.944 10.368 31.968 10.392 ;
    END
  END w_mask_in[62]
  PIN w_mask_in[63]
    DIRECTION INPUT ;
    USE SIGNAL ;
    SHAPE ABUTMENT ;
    PORT
      LAYER M4 ;
      RECT 31.944 10.464 31.968 10.488 ;
    END
  END w_mask_in[63]
  PIN VDD
    DIRECTION INOUT ;
    USE POWER ;
    PORT
      LAYER M4 ;
      RECT 0.300 0.384 31.668 0.480 ;
      RECT 0.300 1.152 31.668 1.248 ;
      RECT 0.300 1.920 31.668 2.016 ;
      RECT 0.300 2.688 31.668 2.784 ;
      RECT 0.300 3.456 31.668 3.552 ;
      RECT 0.300 4.224 31.668 4.320 ;
      RECT 0.300 4.992 31.668 5.088 ;
      RECT 0.300 5.760 31.668 5.856 ;
      RECT 0.300 6.528 31.668 6.624 ;
      RECT 0.300 7.296 31.668 7.392 ;
      RECT 0.300 8.064 31.668 8.160 ;
      RECT 0.300 8.832 31.668 8.928 ;
      RECT 0.300 9.600 31.668 9.696 ;
      RECT 0.300 10.368 31.668 10.464 ;
      RECT 0.300 11.136 31.668 11.232 ;
      RECT 0.300 11.904 31.668 12.000 ;
      RECT 0.300 12.672 31.668 12.768 ;
      RECT 0.300 13.440 31.668 13.536 ;
      RECT 0.300 14.208 31.668 14.304 ;
      RECT 0.300 14.976 31.668 15.072 ;
      RECT 0.300 15.744 31.668 15.840 ;
      RECT 0.300 16.512 31.668 16.608 ;
    END
  END VDD
  PIN VSS
    DIRECTION INOUT ;
    USE GROUND ;
    PORT
      LAYER M4 ;
      RECT 0.300 0.768 31.668 0.864 ;
      RECT 0.300 1.536 31.668 1.632 ;
      RECT 0.300 2.304 31.668 2.400 ;
      RECT 0.300 3.072 31.668 3.168 ;
      RECT 0.300 3.840 31.668 3.936 ;
      RECT 0.300 4.608 31.668 4.704 ;
      RECT 0.300 5.376 31.668 5.472 ;
      RECT 0.300 6.144 31.668 6.240 ;
      RECT 0.300 6.912 31.668 7.008 ;
      RECT 0.300 7.680 31.668 7.776 ;
      RECT 0.300 8.448 31.668 8.544 ;
      RECT 0.300 9.216 31.668 9.312 ;
      RECT 0.300 9.984 31.668 10.080 ;
      RECT 0.300 10.752 31.668 10.848 ;
      RECT 0.300 11.520 31.668 11.616 ;
      RECT 0.300 12.288 31.668 12.384 ;
      RECT 0.300 13.056 31.668 13.152 ;
      RECT 0.300 13.824 31.668 13.920 ;
      RECT 0.300 14.592 31.668 14.688 ;
      RECT 0.300 15.360 31.668 15.456 ;
      RECT 0.300 16.128 31.668 16.224 ;
      RECT 0.300 16.896 31.668 16.992 ;
    END
  END VSS
  OBS
    LAYER M1 ;
    RECT 0 0 31.968 17.280 ;
    LAYER M2 ;
    RECT 0 0 31.968 17.280 ;
    LAYER M3 ;
    RECT 0 0 31.968 17.280 ;
    LAYER M4 ;
    RECT 0.072 0 31.896 17.280 ;
  END
END ot_sram_1r1w_32x64_m1

END LIBRARY
